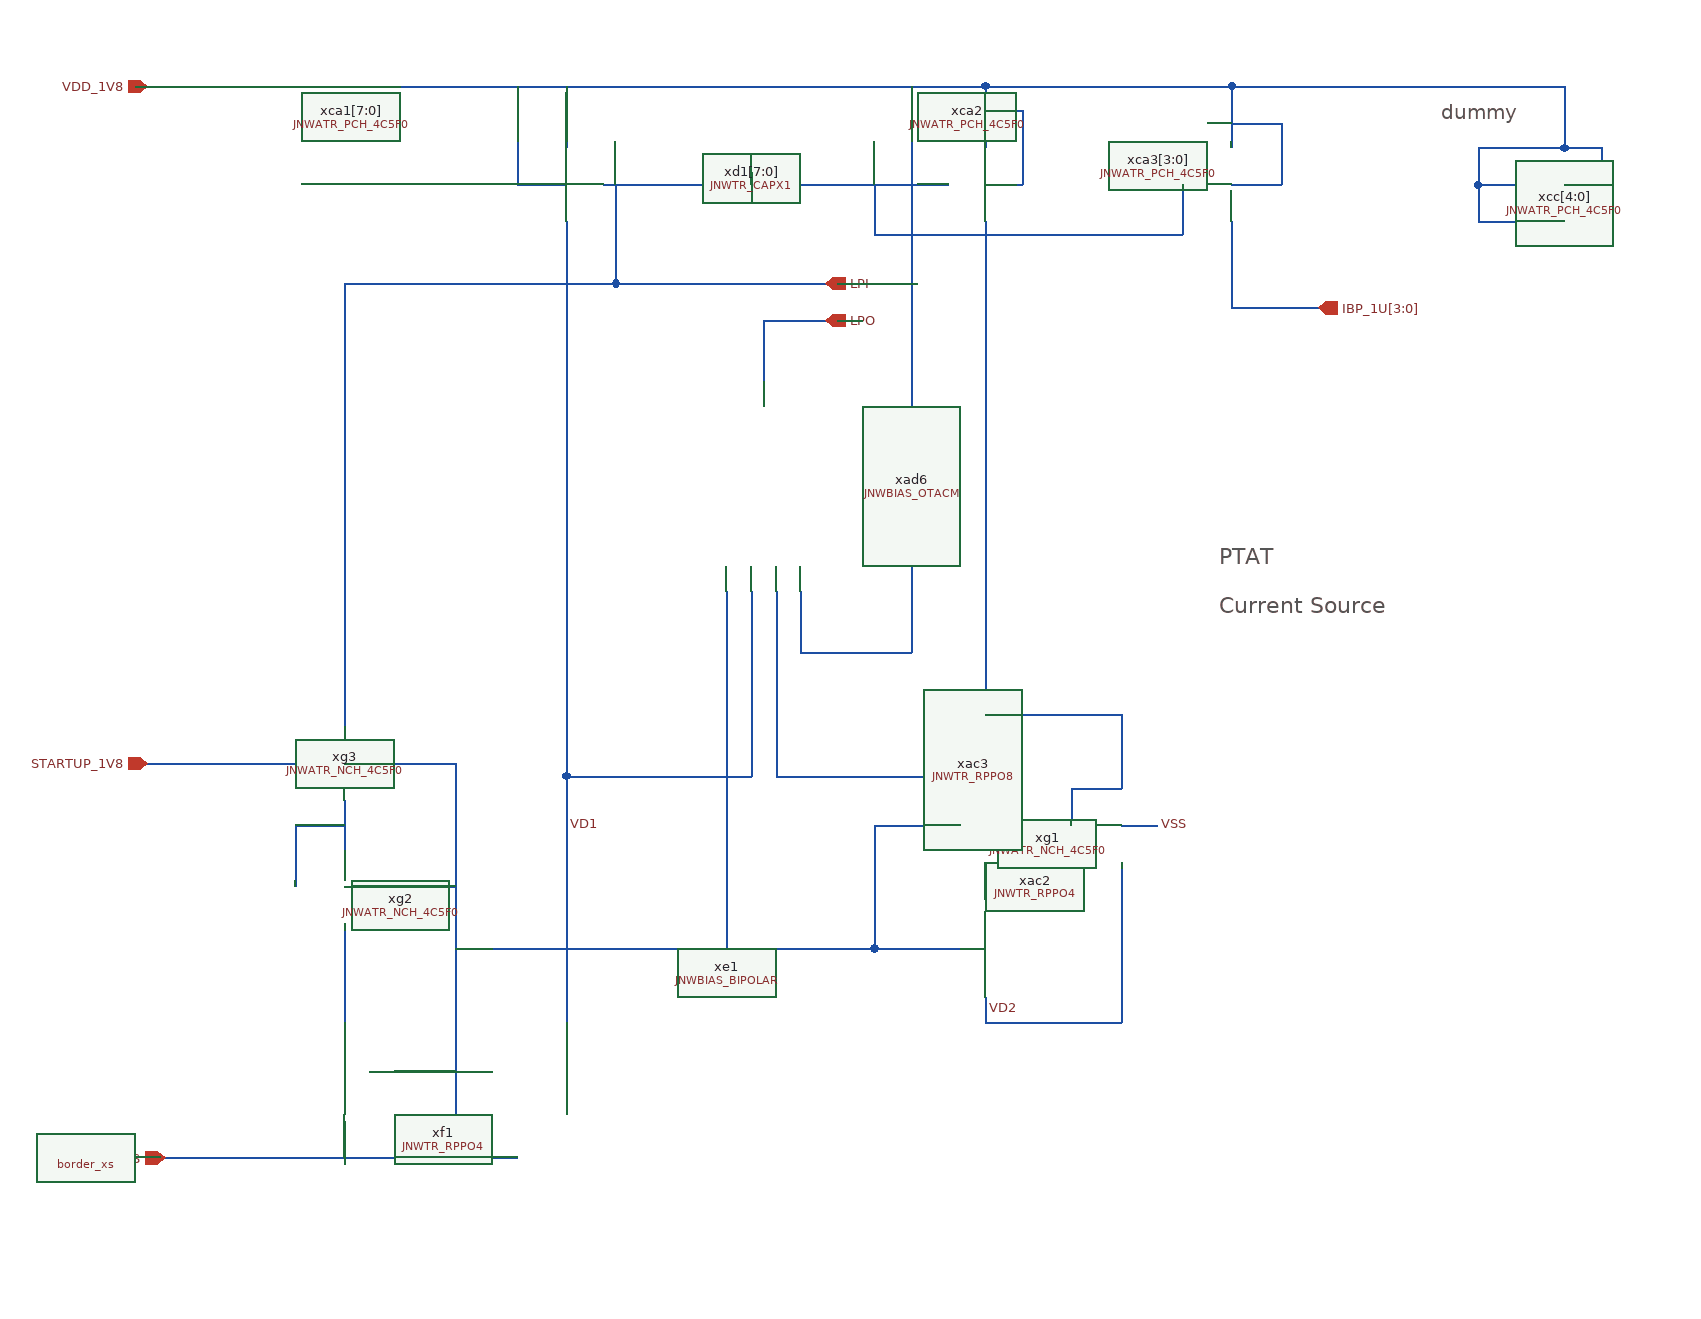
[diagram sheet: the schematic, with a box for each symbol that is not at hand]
v {xschem version=3.4.8RC file_version=1.3}
G {}
K {}
V {}
S {}
F {}
E {}
T {dummy} 1350 -960 0 0 0.5 0.5 {}
T {PTAT
Current Source} 1170 -600 0 0 1 1 {}
N 550 -150 550 -100 {
lab=VSS}
N 890 -370 960 -370 {
lab=VSS}
N 310 -100 550 -100 {
lab=VSS}
N 790 -480 790 -410 {
lab=VD1}
N 840 -780 860 -780 {
lab=LPO}
N 830 -810 860 -810 {
lab=LPI}
N 980 -470 980 -410 {
lab=VR1}
N 810 -410 870 -410 {
lab=VR1}
N 750 -410 790 -410 {
lab=VD1}
N 870 -410 980 -410 {
lab=VR1}
N 800 -780 840 -780 {
lab=LPO}
N 640 -860 640 -410 {
lab=VD1}
N 980 -860 980 -470 {
lab=VR1}
N 800 -810 830 -810 {
lab=LPI}
N 290 -970 310 -970 {
lab=VDD_1V8}
N 340 -970 980 -970 {
lab=VDD_1V8}
N 980 -970 980 -920 {
lab=VDD_1V8}
N 980 -890 1010 -890 {
lab=VDD_1V8}
N 1010 -950 1010 -890 {
lab=VDD_1V8}
N 980 -950 1010 -950 {
lab=VDD_1V8}
N 640 -970 640 -920 {
lab=VDD_1V8}
N 600 -890 640 -890 {
lab=VDD_1V8}
N 600 -970 600 -890 {
lab=VDD_1V8}
N 310 -970 340 -970 {
lab=VDD_1V8}
N 800 -780 800 -730 {
lab=LPO}
N 680 -890 680 -830 {
lab=LPI}
N 670 -890 950 -890 {
lab=LPI}
N 1180 -970 1180 -920 {
lab=VDD_1V8}
N 980 -970 1180 -970 {
lab=VDD_1V8}
N 1180 -890 1220 -890 {
lab=VDD_1V8}
N 1220 -940 1220 -890 {
lab=VDD_1V8}
N 1180 -940 1220 -940 {
lab=VDD_1V8}
N 1140 -890 1140 -850 {
lab=LPI}
N 890 -850 1140 -850 {
lab=LPI}
N 890 -890 890 -850 {
lab=LPI}
N 1180 -790 1250 -790 {
lab=IBP_1U[3:0]}
N 830 -560 830 -510 {
lab=VDD_1V8}
N 810 -480 810 -410 {
lab=VR1}
N 810 -560 810 -480 {
lab=VR1}
N 790 -560 790 -480 {
lab=VD1}
N 980 -330 980 -310 {lab=#net1}
N 890 -270 960 -270 {lab=VSS}
N 1180 -860 1180 -790 {lab=IBP_1U[3:0]}
N 460 -420 550 -420 {lab=VSS}
N 360 -420 420 -420 {lab=STARTUP_1V8}
N 460 -390 460 -350 {lab=#net2}
N 460 -130 460 -100 {lab=VSS}
N 480 -170 550 -170 {lab=VSS}
N 300 -420 360 -420 {lab=STARTUP_1V8}
N 550 -280 550 -150 {lab=VSS}
N 790 -900 790 -890 {lab=LPI}
N 680 -830 680 -810 {lab=LPI}
N 680 -810 800 -810 {lab=LPI}
N 770 -560 770 -510 {lab=VSS}
N 640 -410 640 -210 {lab=VD1}
N 640 -410 750 -410 {lab=VD1}
N 550 -100 600 -100 {lab=VSS}
N 980 -230 980 -210 {lab=VD2}
N 460 -810 680 -810 {lab=LPI}
N 460 -810 460 -450 {lab=LPI}
N 890 -370 890 -270 {lab=VSS}
N 550 -270 890 -270 {lab=VSS}
N 1090 -370 1120 -370 {lab=VSS}
N 1050 -400 1050 -370 {lab=VR1}
N 1050 -400 1090 -400 {lab=VR1}
N 980 -460 1090 -460 {lab=VR1}
N 980 -210 1090 -210 {lab=VD2}
N 460 -320 550 -320 {lab=VSS}
N 460 -290 460 -210 {lab=#net3}
N 420 -370 420 -320 {lab=#net2}
N 420 -370 460 -370 {lab=#net2}
N 550 -420 550 -280 {lab=VSS}
N 770 -510 770 -270 {lab=VSS}
N 920 -970 920 -510 {lab=VDD_1V8}
N 830 -510 920 -510 {lab=VDD_1V8}
N 1090 -460 1090 -400 {lab=VR1}
N 1090 -340 1090 -210 {lab=VD2}
N 1380 -890 1410 -890 {lab=VDD_1V8}
N 1380 -920 1380 -890 {lab=VDD_1V8}
N 1380 -920 1450 -920 {lab=VDD_1V8}
N 1450 -890 1480 -890 {lab=VDD_1V8}
N 1480 -920 1480 -890 {lab=VDD_1V8}
N 1450 -920 1480 -920 {lab=VDD_1V8}
N 1380 -860 1450 -860 {lab=VDD_1V8}
N 1380 -890 1380 -860 {lab=VDD_1V8}
N 1450 -970 1450 -920 {lab=VDD_1V8}
N 1180 -970 1450 -970 {lab=VDD_1V8}
C {devices/ipin.sym} 300 -970 0 0 {name=p4 lab=VDD_1V8}
C {devices/ipin.sym} 313.9889709803555 -100 0 0 {name=p5 lab=VSS}
C {devices/opin.sym} 850 -810 0 0 {name=p7 lab=LPI}
C {devices/opin.sym} 850 -780 0 0 {name=p8 lab=LPO}
C {devices/opin.sym} 1250 -790 0 0 {name=p9 lab=IBP_1U[3:0]}
C {devices/lab_pin.sym} 640 -370 0 1 {name=l2 sig_type=std_logic lab=VD1}
C {devices/lab_pin.sym} 980 -220 0 1 {name=l4 sig_type=std_logic lab=VD2}
C {devices/lab_pin.sym} 980 -430 0 1 {name=l5 sig_type=std_logic lab=VR1}
C {JNW_ATR_SKY130A/JNWATR_PCH_4C5F0.sym} 940 -890 0 0 {name=xca2}
C {JNW_ATR_SKY130A/JNWATR_PCH_4C5F0.sym} 680 -890 0 1 {name=xca1[7:0]}
C {JNW_TR_SKY130A/JNWTR_CAPX1.sym} 790 -960 2 1 {name=xd1[7:0]}
C {JNW_BIAS_SKY130A/JNWBIAS_OTACM.sym} 800 -710 1 1 {name=xad6}
C {JNW_ATR_SKY130A/JNWATR_PCH_4C5F0.sym} 1140 -890 0 0 {name=xca3[3:0]}
C {JNW_TR_SKY130A/JNWTR_RPPO4.sym} 980 -310 1 0 {name=xac2}
C {cborder/border_xs.sym} 340 -40 0 0 {user="Carsten Wulff" company="Carsten Wulff Software"}
C {devices/ipin.sym} 300 -420 0 0 {name=p1 lab=STARTUP_1V8}
C {JNW_ATR_SKY130A/JNWATR_NCH_4C5F0.sym} 420 -420 0 0 {name=xg3 }
C {JNW_TR_SKY130A/JNWTR_RPPO4.sym} 460 -210 3 1 {name=xf1}
C {JNW_BIAS_SKY130A/JNWBIAS_BIPOLAR.sym} 800 -110 0 0 {name=xe1}
C {JNW_ATR_SKY130A/JNWATR_NCH_4C5F0.sym} 1050 -370 0 0 {name=xg1 }
C {devices/lab_pin.sym} 1120 -370 0 1 {name=l1 sig_type=std_logic lab=VSS}
C {JNW_ATR_SKY130A/JNWATR_NCH_4C5F0.sym} 420 -320 0 0 {name=xg2 }
C {JNW_TR_SKY130A/JNWTR_RPPO8.sym} 980 -410 1 0 {name=xac3}
C {JNW_ATR_SKY130A/JNWATR_PCH_4C5F0.sym} 1410 -890 0 0 {name=xcc[4:0]}
